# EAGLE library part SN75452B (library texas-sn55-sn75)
NAND PERIPHERAL DRIVERS FOR HIGH-CURRENT SWITCHING AT VERY HIGH SPEEDS Source: www.ti.com sn75452b.pdf

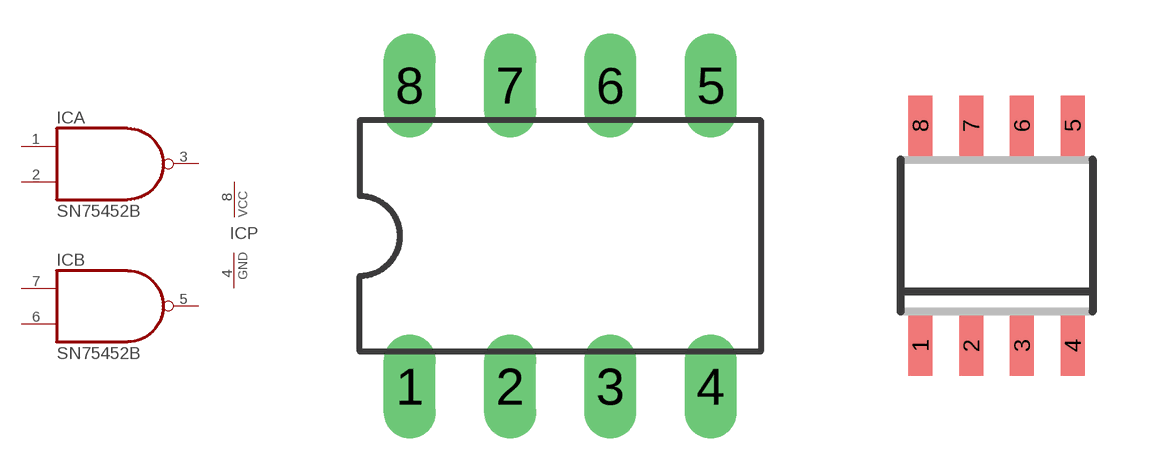
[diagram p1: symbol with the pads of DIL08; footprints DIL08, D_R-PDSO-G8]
Designator prefix IC; gates A=NAND B=NAND P=PWRN

## SN75452BP  [DIL08]
1  A:I0  in
2  A:I1  in
3  A:O  out
4  P:GND  pwr
5  B:O  out
6  B:I1  in
7  B:I0  in
8  P:VCC  pwr

## SN75452BJG  [DIL08]
Pads as for DIL08

## SN75452BD  [D_R-PDSO-G8]
Pads as for DIL08

## SN75452BPS  [PS_R-PDSO-G8]
Pads as for DIL08

## Footprint DIL08 (pad centres in mm)
Dual In Line Package
drill 0.813 long: 1 -3.81,-3.81; 2 -1.27,-3.81; 3 1.27,-3.81; 4 3.81,-3.81; 5 3.81,3.81; 6 1.27,3.81; 7 -1.27,3.81; 8 -3.81,3.81

## Footprint D_R-PDSO-G8 (pad centres in mm)
D (R-PDSO-G8) Source: http://focus.ti.com/lit/ds/slos063b/slos063b.pdf
smd 0.6 x 1.5: 1 -1.905,-2.75; 2 -0.635,-2.75; 3 0.635,-2.75; 4 1.905,-2.75; 5 1.905,2.75; 6 0.635,2.75; 7 -0.635,2.75; 8 -1.905,2.75

## Footprint PS_R-PDSO-G8 (pad centres in mm)
PS (R-PDSO-G8) Source: www.ti.com sn75452b.pdf
smd 0.6 x 1.5: 1 -1.905,-3.685; 2 -0.635,-3.685; 3 0.635,-3.685; 4 1.905,-3.685; 5 1.905,3.7; 6 0.635,3.7; 7 -0.635,3.7; 8 -1.905,3.7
